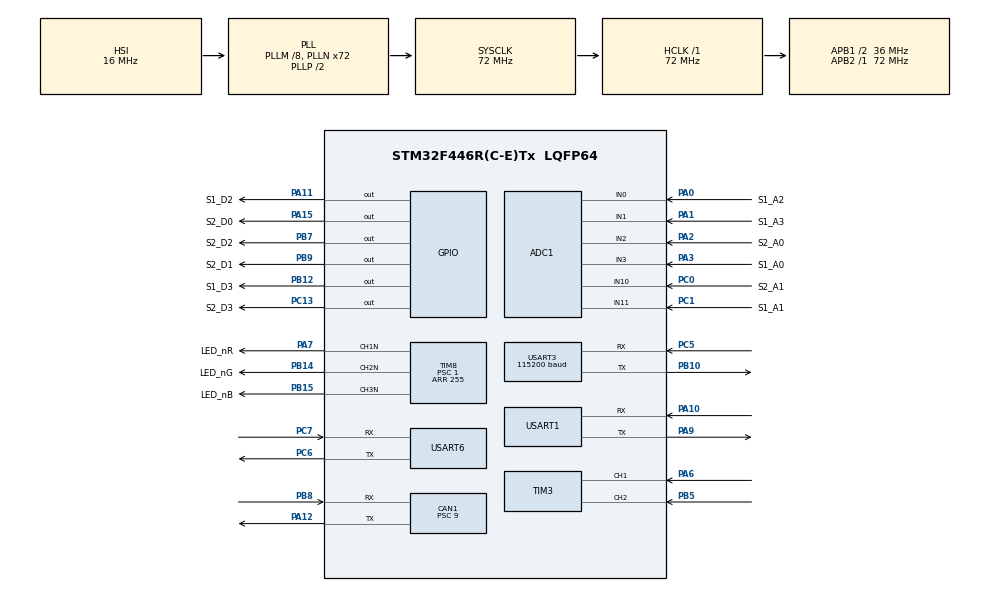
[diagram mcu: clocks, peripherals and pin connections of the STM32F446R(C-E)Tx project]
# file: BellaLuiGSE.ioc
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Dma.ADC1.4.FIFOMode=DMA_FIFOMODE_DISABLE
CAN1.NART=DISABLE
Dma.ADC1.4.Priority=DMA_PRIORITY_LOW
PH0-OSC_IN.Signal=RCC_OSC_IN
PB10.GPIO_PuPd=GPIO_PULLUP
PB10.Mode=Asynchronous
PA10.GPIO_PuPd=GPIO_PULLUP
Dma.USART3_TX.3.MemInc=DMA_MINC_ENABLE
ADC1.SamplingTime-6\#ChannelRegularConversion=ADC_SAMPLETIME_144CYCLES
PB14.GPIO_Label=LED_nG
PC5.Mode=Asynchronous
Dma.USART3_TX.3.MemDataAlignment=DMA_MDATAALIGN_BYTE
Dma.ADC1.4.PeriphInc=DMA_PINC_DISABLE
RCC.SYSCLKSource=RCC_SYSCLKSOURCE_PLLCLK
TIM8.OCNPolarity_1=TIM_OCNPOLARITY_LOW
Dma.USART3_RX.2.Priority=DMA_PRIORITY_LOW
TIM8.OCNPolarity_2=TIM_OCNPOLARITY_LOW
FREERTOS.configENABLE_FPU=1
USART3.BaudRate=115200
Dma.USART1_TX.0.Direction=DMA_MEMORY_TO_PERIPH
ADC1.Channel-5\#ChannelRegularConversion=ADC_CHANNEL_10
TIM8.OCNPolarity_3=TIM_OCNPOLARITY_LOW
RCC.APB2TimFreq_Value=72000000
ADC1.Channel-2\#ChannelRegularConversion=ADC_CHANNEL_3
PC7.Signal=USART6_RX
VP_TIM3_VS_ControllerModeClock.Mode=Clock Mode
Dma.ADC1.4.Instance=DMA2_Stream0
FREERTOS.configMINIMAL_STACK_SIZE=256
Dma.USART1_RX.1.PeriphDataAlignment=DMA_PDATAALIGN_BYTE
NVIC.TIM8_TRG_COM_TIM14_IRQn=true\:0\:0\:false\:false\:true\:false\:false\:true
PB3.Mode=Trace_Asynchronous_SW
PB12.GPIO_Label=S1_D3
TIM8.OCMode_PWM-PWM\ Generation2\ CH2N=TIM_OCMODE_PWM1
TIM8.OCMode_PWM-PWM\ Generation1\ CH1N=TIM_OCMODE_PWM1
PB14.Mode=PWM Generation2 CH2N
VP_FREERTOS_VS_CMSIS_V1.Mode=CMSIS_V1
VP_SYS_VS_tim14.Mode=TIM14
Dma.USART1_TX.0.PeriphDataAlignment=DMA_PDATAALIGN_BYTE
VP_TIM1_VS_ClockSourceINT.Mode=Internal
Dma.USART1_RX.1.Mode=DMA_CIRCULAR
CAN1.Prescaler=9
Mcu.Package=LQFP64
PB9.Signal=GPIO_Output
NVIC.TimeBase=TIM8_TRG_COM_TIM14_IRQn
NVIC.TimeBaseIP=TIM14
PA10.Signal=USART1_RX
Dma.ADC1.4.MemInc=DMA_MINC_ENABLE
PC6.GPIO_PuPd=GPIO_PULLUP
Dma.USART1_RX.1.PeriphInc=DMA_PINC_DISABLE
NVIC.DMA2_Stream2_IRQn=true\:5\:0\:false\:false\:true\:false\:false\:true
RCC.APB1TimFreq_Value=72000000
NVIC.USART1_IRQn=true\:0\:0\:false\:false\:true\:true\:true\:true
ADC1.Rank-4\#ChannelRegularConversion=3
CAN1.CalculateTimeQuantum=250.0
Dma.USART1_RX.1.Instance=DMA2_Stream2
Dma.USART1_RX.1.MemDataAlignment=DMA_MDATAALIGN_BYTE
FREERTOS.Tasks01=defaultTask,0,256,StartDefaultTask,Default,NULL,Dynamic,NULL,NULL
TIM3.Channel-Input_Capture2_from_TI2=TIM_CHANNEL_2
PC13.Signal=GPIO_Output
PC6.Signal=USART6_TX
PA11.GPIO_Label=S1_D2
PC0.Signal=ADCx_IN10
RCC.APB1CLKDivider=RCC_HCLK_DIV2
PC14-OSC32_IN.Signal=RCC_OSC32_IN
Dma.USART3_TX.3.PeriphInc=DMA_PINC_DISABLE
PA0-WKUP.GPIO_Label=S1_A2
PA0-WKUP.Signal=ADCx_IN0
ADC1.Channel-7\#ChannelRegularConversion=ADC_CHANNEL_1
Dma.USART3_RX.2.PeriphDataAlignment=DMA_PDATAALIGN_BYTE
PC6.Mode=Asynchronous
TIM8.Channel-PWM\ Generation3\ CH3N=TIM_CHANNEL_3
PA9.Signal=USART1_TX
VP_TIM8_VS_ClockSourceINT.Mode=Internal
PC7.GPIO_PuPd=GPIO_PULLUP
PB10.Signal=USART3_TX
PB14.Signal=TIM8_CH2N
Dma.USART1_RX.1.FIFOMode=DMA_FIFOMODE_DISABLE
FREERTOS.MEMORY_ALLOCATION=0
PB15.GPIO_Label=LED_nB
PA1.GPIO_Label=S1_A3
Dma.ADC1.4.Mode=DMA_CIRCULAR
ADC1.DMAContinuousRequests=ENABLE
PA13.Mode=Trace_Asynchronous_SW
Dma.ADC1.4.MemDataAlignment=DMA_MDATAALIGN_HALFWORD
Dma.USART3_TX.3.Mode=DMA_NORMAL
TIM8.Period=255
PB5.Signal=S_TIM3_CH2
ADC1.master=1
USART1.VirtualMode=VM_ASYNC
PA11.Signal=GPIO_Output
ProjectManager.HeapSize=0x200
ADC1.SamplingTime-5\#ChannelRegularConversion=ADC_SAMPLETIME_144CYCLES
NVIC.PriorityGroup=NVIC_PRIORITYGROUP_4
PB8.Mode=Master
Dma.USART1_RX.1.Direction=DMA_PERIPH_TO_MEMORY
ADC1.Rank-5\#ChannelRegularConversion=4
PC1.Signal=ADCx_IN11
NVIC.CAN1_RX0_IRQn=true\:0\:0\:false\:false\:true\:true\:true\:true
Dma.USART3_TX.3.Priority=DMA_PRIORITY_LOW
Mcu.Family=STM32F4
RCC.CortexFreq_Value=72000000
Dma.USART3_TX.3.PeriphDataAlignment=DMA_PDATAALIGN_BYTE
ADC1.ContinuousConvMode=ENABLE
SH.ADCx_IN2.0=ADC1_IN2,IN2
VP_IWDG_VS_IWDG.Mode=IWDG_Activate
PC0.GPIO_Label=S2_A1
PC13.GPIO_Label=S2_D3
PB15.Signal=TIM8_CH3N
ProjectManager.StackSize=0x400
PA15.GPIO_Label=S2_D0
Dma.USART1_TX.0.Priority=DMA_PRIORITY_LOW
PA12.Signal=CAN1_TX
ADC1.Channel-3\#ChannelRegularConversion=ADC_CHANNEL_11
Dma.USART3_RX.2.PeriphInc=DMA_PINC_DISABLE
RCC.HCLKFreq_Value=72000000
SH.ADCx_IN3.0=ADC1_IN3,IN3
NVIC.DMA2_Stream0_IRQn=true\:0\:0\:false\:false\:true\:true\:false\:true
Dma.USART1_RX.1.MemInc=DMA_MINC_ENABLE
RCC.AHBFreq_Value=72000000
PH0-OSC_IN.Mode=HSE-External-Oscillator
RCC.HSE_VALUE=8000000
ADC1.SamplingTime-4\#ChannelRegularConversion=ADC_SAMPLETIME_144CYCLES
ADC1.Channel-6\#ChannelRegularConversion=ADC_CHANNEL_0
ADC1.Rank-2\#ChannelRegularConversion=1
Dma.USART3_TX.3.Direction=DMA_MEMORY_TO_PERIPH
PC14-OSC32_IN.Mode=LSE-External-Oscillator
PA14.Mode=Trace_Asynchronous_SW
TIM8.Pulse-PWM\ Generation2\ CH2N=128
PB7.Signal=GPIO_Output
SH.ADCx_IN0.0=ADC1_IN0,IN0
SH.S_TIM3_CH1.0=TIM3_CH1,TriggerSource_TI1FP1
FREERTOS.configTOTAL_HEAP_SIZE=30720
PB7.GPIO_Label=S2_D2
PH1-OSC_OUT.Mode=HSE-External-Oscillator
PA6.Signal=S_TIM3_CH1
NVIC.DMA2_Stream7_IRQn=true\:5\:0\:false\:false\:true\:false\:true\:true
USART6.VirtualMode=VM_ASYNC
PA2.GPIO_Label=S2_A0
IWDG.Reload=2000
TIM8.Channel-PWM\ Generation2\ CH2N=TIM_CHANNEL_2
PA15.Signal=GPIO_Output
Dma.USART1_TX.0.Instance=DMA2_Stream7
Dma.USART1_TX.0.FIFOMode=DMA_FIFOMODE_DISABLE
TIM8.Prescaler=1
SH.ADCx_IN1.0=ADC1_IN1,IN1
Dma.Request2=USART3_RX
Dma.Request1=USART1_RX
Dma.Request4=ADC1
Dma.Request3=USART3_TX
PC5.Signal=USART3_RX
Dma.USART1_RX.1.Priority=DMA_PRIORITY_LOW
ADC1.Rank-6\#ChannelRegularConversion=5
Dma.Request0=USART1_TX
TIM8.Pulse-PWM\ Generation1\ CH1N=128
PA3.Signal=ADCx_IN3
PC15-OSC32_OUT.Mode=LSE-External-Oscillator
Dma.USART1_TX.0.MemInc=DMA_MINC_ENABLE
PA7.Mode=PWM Generation1 CH1N
Dma.USART1_TX.0.PeriphInc=DMA_PINC_DISABLE
ADC1.Channel-4\#ChannelRegularConversion=ADC_CHANNEL_2
PB9.GPIO_Label=S2_D1
PA10.Mode=Asynchronous
Dma.USART3_RX.2.Mode=DMA_CIRCULAR
Dma.ADC1.4.PeriphDataAlignment=DMA_PDATAALIGN_HALFWORD
NVIC.DMA1_Stream1_IRQn=true\:5\:0\:false\:false\:true\:false\:true\:true
PC5.GPIO_PuPd=GPIO_PULLUP
PA9.GPIO_PuPd=GPIO_PULLUP
ADC1.SamplingTime-2\#ChannelRegularConversion=ADC_SAMPLETIME_144CYCLES
TIM8.Channel-PWM\ Generation1\ CH1N=TIM_CHANNEL_1
PA13.Signal=SYS_JTMS-SWDIO
PA9.Mode=Asynchronous
Dma.USART3_RX.2.MemInc=DMA_MINC_ENABLE
CAN1.BS2=CAN_BS2_2TQ
CAN1.BS1=CAN_BS1_13TQ
ProjectManager.TargetToolchain=STM32CubeIDE
Dma.USART3_TX.3.FIFOMode=DMA_FIFOMODE_DISABLE
RCC.USBFreq_Value=72000000
Dma.USART3_RX.2.Direction=DMA_PERIPH_TO_MEMORY
PC15-OSC32_OUT.Signal=RCC_OSC32_OUT
PA1.Signal=ADCx_IN1
SH.S_TIM3_CH2.0=TIM3_CH2,Input_Capture2_from_TI2
Dma.USART3_TX.3.Instance=DMA1_Stream3
Dma.USART1_TX.0.Mode=DMA_NORMAL
board=custom
RCC.VCOOutputFreq_Value=144000000
TIM8.OCMode_PWM-PWM\ Generation3\ CH3N=TIM_OCMODE_PWM1
PB15.Mode=PWM Generation3 CH3N
RCC.APB2Freq_Value=72000000
SH.ADCx_IN11.0=ADC1_IN11,IN11
TIM8.Pulse-PWM\ Generation3\ CH3N=128
PC1.GPIO_Label=S1_A1
PH1-OSC_OUT.Signal=RCC_OSC_OUT
ADC1.NbrOfConversion=6
Mcu.Name=STM32F446R(C-E)Tx
PA2.Signal=ADCx_IN2
PB3.Signal=SYS_JTDO-SWO
RCC.SYSCLKFreq_VALUE=72000000
PA7.GPIO_Label=LED_nR
PA12.Mode=Master
ADC1.Rank-3\#ChannelRegularConversion=2
ADC1.SamplingTime-3\#ChannelRegularConversion=ADC_SAMPLETIME_144CYCLES
USART3.VirtualMode=VM_ASYNC
Dma.USART1_TX.0.MemDataAlignment=DMA_MDATAALIGN_BYTE
PA14.Signal=SYS_JTCK-SWCLK
SH.ADCx_IN10.0=ADC1_IN10,IN10
Dma.USART3_RX.2.FIFOMode=DMA_FIFOMODE_DISABLE
Dma.ADC1.4.Direction=DMA_PERIPH_TO_MEMORY
ADC1.Rank-7\#ChannelRegularConversion=6
Dma.USART3_RX.2.MemDataAlignment=DMA_MDATAALIGN_BYTE
ADC1.NbrOfConversionFlag=1
RCC.PLLM=8
RCC.PLLN=72
PB8.Signal=CAN1_RX
NVIC.DMA1_Stream3_IRQn=true\:5\:0\:false\:false\:true\:false\:true\:true
ADC1.SamplingTime-7\#ChannelRegularConversion=ADC_SAMPLETIME_144CYCLES
Dma.USART3_RX.2.Instance=DMA1_Stream1
PC7.Mode=Asynchronous
RCC.APB1Freq_Value=36000000
VP_CRC_VS_CRC.Mode=CRC_Activate
PB12.Signal=GPIO_Output
PA3.GPIO_Label=S1_A0
PA7.Signal=TIM8_CH1N

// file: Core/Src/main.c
/* USER CODE BEGIN Header */
/**
  ******************************************************************************
  * @file           : main.c
  * @brief          : Main program body
  ******************************************************************************
  * @attention
  *
  * <h2><center>&copy; Copyright (c) 2021 STMicroelectronics.
  * All rights reserved.</center></h2>
  *
  * This software component is licensed by ST under BSD 3-Clause license,
  * the "License"; You may not use this file except in compliance with the
  * License. You may obtain a copy of the License at:
  *                        opensource.org/licenses/BSD-3-Clause
  *
  ******************************************************************************
  */
/* USER CODE END Header */
#include "main.h"
#include "cmsis_os.h"
#include "FreeRTOS.h"

/* USER CODE BEGIN Includes */
#include "thread_init.h"
#include "can_transmission.h"
#include "debug/led.h"
#include "debug/console.h"
#include "debug/shell.h"
#include "debug/terminal.h"
/* USER CODE END Includes */

ADC_HandleTypeDef hadc1;
DMA_HandleTypeDef hdma_adc1;

CAN_HandleTypeDef hcan1;

CRC_HandleTypeDef hcrc;

TIM_HandleTypeDef htim1;
TIM_HandleTypeDef htim3;
TIM_HandleTypeDef htim8;

UART_HandleTypeDef huart1;
UART_HandleTypeDef huart3;
UART_HandleTypeDef huart6;
DMA_HandleTypeDef hdma_usart1_tx;
DMA_HandleTypeDef hdma_usart1_rx;
DMA_HandleTypeDef hdma_usart3_rx;
DMA_HandleTypeDef hdma_usart3_tx;

osThreadId defaultTaskHandle;

void SystemClock_Config(void);
static void MX_GPIO_Init(void);
static void MX_DMA_Init(void);
static void MX_CAN1_Init(void);
static void MX_USART1_UART_Init(void);
static void MX_USART3_UART_Init(void);
static void MX_TIM1_Init(void);
static void MX_TIM3_Init(void);
static void MX_TIM8_Init(void);
static void MX_USART6_UART_Init(void);
static void MX_ADC1_Init(void);
static void MX_CRC_Init(void);
static void MX_IWDG_Init(void);
void StartDefaultTask(void const * argument);

int main(void)
{

  /* MCU Configuration--------------------------------------------------------*/

  /* Reset of all peripherals, Initializes the Flash interface and the Systick. */
  HAL_Init();

  /* Configure the system clock */
  SystemClock_Config();

  /* Initialize all configured peripherals */
  MX_GPIO_Init();
  MX_DMA_Init();
  MX_CAN1_Init();
  MX_USART1_UART_Init();
  MX_USART3_UART_Init();
  MX_TIM1_Init();
  MX_TIM3_Init();
  MX_TIM8_Init();
  MX_USART6_UART_Init();
  MX_ADC1_Init();
  MX_CRC_Init();
  MX_IWDG_Init();
  /* USER CODE BEGIN 2 */
  rocket_log_init(&huart3);
  shell_init(&huart3, &terminal_execute);

  rocket_boot_log("BellaLui v1.0\n\n");

  led_init();
  led_set_rgb(127, 255, 255);

  CAN_Config(CAN_ID); // A changer en fonction de la board
  /* USER CODE END 2 */

  /* Create the thread(s) */
  /* definition and creation of defaultTask */
  osThreadDef(defaultTask, StartDefaultTask, osPriorityNormal, 0, 256);
  defaultTaskHandle = osThreadCreate(osThread(defaultTask), NULL);

  /* USER CODE BEGIN RTOS_THREADS */
  /* add threads, ... */
  create_threads();

  /* USER CODE END RTOS_THREADS */

  /* Start scheduler */
  osKernelStart();

  /* We should never get here as control is now taken by the scheduler */
  /* Infinite loop */
  while (1)
  {

  }
}

void SystemClock_Config(void)
{
  RCC_OscInitTypeDef RCC_OscInitStruct = {0};
  RCC_ClkInitTypeDef RCC_ClkInitStruct = {0};

  /** Configure the main internal regulator output voltage
  */
  __HAL_RCC_PWR_CLK_ENABLE();
  __HAL_PWR_VOLTAGESCALING_CONFIG(PWR_REGULATOR_VOLTAGE_SCALE3);
  /** Initializes the RCC Oscillators according to the specified parameters
  * in the RCC_OscInitTypeDef structure.
  */
  RCC_OscInitStruct.OscillatorType = RCC_OSCILLATORTYPE_HSI|RCC_OSCILLATORTYPE_LSI;
  RCC_OscInitStruct.HSIState = RCC_HSI_ON;
  RCC_OscInitStruct.HSICalibrationValue = RCC_HSICALIBRATION_DEFAULT;
  RCC_OscInitStruct.LSIState = RCC_LSI_ON;
  RCC_OscInitStruct.PLL.PLLState = RCC_PLL_ON;
  RCC_OscInitStruct.PLL.PLLSource = RCC_PLLSOURCE_HSI;
  RCC_OscInitStruct.PLL.PLLM = 8;
  RCC_OscInitStruct.PLL.PLLN = 72;
  RCC_OscInitStruct.PLL.PLLP = RCC_PLLP_DIV2;
  RCC_OscInitStruct.PLL.PLLQ = 2;
  RCC_OscInitStruct.PLL.PLLR = 2;
  if (HAL_RCC_OscConfig(&RCC_OscInitStruct) != HAL_OK)
  {
    Error_Handler();
  }
  /** Initializes the CPU, AHB and APB buses clocks
  */
  RCC_ClkInitStruct.ClockType = RCC_CLOCKTYPE_HCLK|RCC_CLOCKTYPE_SYSCLK
                              |RCC_CLOCKTYPE_PCLK1|RCC_CLOCKTYPE_PCLK2;
  RCC_ClkInitStruct.SYSCLKSource = RCC_SYSCLKSOURCE_PLLCLK;
  RCC_ClkInitStruct.AHBCLKDivider = RCC_SYSCLK_DIV1;
  RCC_ClkInitStruct.APB1CLKDivider = RCC_HCLK_DIV2;
  RCC_ClkInitStruct.APB2CLKDivider = RCC_HCLK_DIV1;

  if (HAL_RCC_ClockConfig(&RCC_ClkInitStruct, FLASH_LATENCY_2) != HAL_OK)
  {
    Error_Handler();
  }
}

static void MX_ADC1_Init(void)
{

  ADC_ChannelConfTypeDef sConfig = {0};

  /** Configure the global features of the ADC (Clock, Resolution, Data Alignment and number of conversion)
  */
  hadc1.Instance = ADC1;
  hadc1.Init.ClockPrescaler = ADC_CLOCK_SYNC_PCLK_DIV2;
  hadc1.Init.Resolution = ADC_RESOLUTION_12B;
  hadc1.Init.ScanConvMode = ENABLE;
  hadc1.Init.ContinuousConvMode = ENABLE;
  hadc1.Init.DiscontinuousConvMode = DISABLE;
  hadc1.Init.ExternalTrigConvEdge = ADC_EXTERNALTRIGCONVEDGE_NONE;
  hadc1.Init.ExternalTrigConv = ADC_SOFTWARE_START;
  hadc1.Init.DataAlign = ADC_DATAALIGN_RIGHT;
#ifdef HB1_SENSOR_TELEMETRY_BOARD
  hadc1.Init.NbrOfConversion = 6;
#endif
 #ifdef HB2_CODE_BOARD
  hadc1.Init.NbrOfConversion = 2;
#endif
#ifdef HB3_POWER_BOARD
  hadc1.Init.NbrOfConversion = 4;
#endif
  hadc1.Init.DMAContinuousRequests = ENABLE;
  hadc1.Init.EOCSelection = ADC_EOC_SINGLE_CONV;
  if (HAL_ADC_Init(&hadc1) != HAL_OK)
  {
    Error_Handler();
  }
  /** Configure for the selected ADC regular channel its corresponding rank in the sequencer and its sample time.
  */
  sConfig.Channel = ADC_CHANNEL_3;
  sConfig.Rank = 1;
  sConfig.SamplingTime = ADC_SAMPLETIME_144CYCLES;
  if (HAL_ADC_ConfigChannel(&hadc1, &sConfig) != HAL_OK)
  {
    Error_Handler();
  }
  /** Configure for the selected ADC regular channel its corresponding rank in the sequencer and its sample time.
  */
  sConfig.Channel = ADC_CHANNEL_11;
  sConfig.Rank = 2;
  sConfig.SamplingTime = ADC_SAMPLETIME_144CYCLES;
  if (HAL_ADC_ConfigChannel(&hadc1, &sConfig) != HAL_OK)
  {
    Error_Handler();
  }
  /** Configure for the selected ADC regular channel its corresponding rank in the sequencer and its sample time.
  */
#if defined (HB3_POWER_BOARD) || defined (HB1_SENSOR_TELEMETRY_BOARD)
  sConfig.Channel = ADC_CHANNEL_2;
  sConfig.Rank = 3;
  sConfig.SamplingTime = ADC_SAMPLETIME_144CYCLES;
  if (HAL_ADC_ConfigChannel(&hadc1, &sConfig) != HAL_OK)
  {
    Error_Handler();
  }
  /** Configure for the selected ADC regular channel its corresponding rank in the sequencer and its sample time.
  */
  sConfig.Channel = ADC_CHANNEL_10;
  sConfig.Rank = 4;
  sConfig.SamplingTime = ADC_SAMPLETIME_144CYCLES;
  if(HAL_ADC_ConfigChannel(&hadc1, &sConfig) != HAL_OK)
  {
    Error_Handler();
  }
#endif
  /** Configure for the selected ADC regular channel its corresponding rank in the sequencer and its sample time.
  */
#ifdef HB1_SENSOR_TELEMETRY_BOARD
  sConfig.Channel = ADC_CHANNEL_0;
  sConfig.Rank = 5;
  sConfig.SamplingTime = ADC_SAMPLETIME_144CYCLES;
  if (HAL_ADC_ConfigChannel(&hadc1, &sConfig) != HAL_OK)
  {
    Error_Handler();
  }
  /** Configure for the selected ADC regular channel its corresponding rank in the sequencer and its sample time.
  */
  sConfig.Channel = ADC_CHANNEL_1;
  sConfig.Rank = 6;
  sConfig.SamplingTime = ADC_SAMPLETIME_144CYCLES;
  if (HAL_ADC_ConfigChannel(&hadc1, &sConfig) != HAL_OK)
  {
    Error_Handler();
  }
#endif

}

static void MX_CAN1_Init(void)
{

  hcan1.Instance = CAN1;
  hcan1.Init.Prescaler = 9;
  hcan1.Init.Mode = CAN_MODE_NORMAL;
  hcan1.Init.SyncJumpWidth = CAN_SJW_1TQ;
  hcan1.Init.TimeSeg1 = CAN_BS1_13TQ;
  hcan1.Init.TimeSeg2 = CAN_BS2_2TQ;
  hcan1.Init.TimeTriggeredMode = DISABLE;
  hcan1.Init.AutoBusOff = DISABLE;
  hcan1.Init.AutoWakeUp = DISABLE;
  hcan1.Init.AutoRetransmission = DISABLE;
  hcan1.Init.ReceiveFifoLocked = DISABLE;
  hcan1.Init.TransmitFifoPriority = DISABLE;
  if (HAL_CAN_Init(&hcan1) != HAL_OK)
  {
    Error_Handler();
  }

}

static void MX_CRC_Init(void)
{

  hcrc.Instance = CRC;
  if (HAL_CRC_Init(&hcrc) != HAL_OK)
  {
    Error_Handler();
  }

}

static void MX_IWDG_Init(void)
{

// Setup for 1s reset
  hiwdg.Instance = IWDG;
  hiwdg.Init.Prescaler = IWDG_PRESCALER_8;
  hiwdg.Init.Reload = 200;
  if (HAL_IWDG_Init(&hiwdg) != HAL_OK)
  {
    Error_Handler();
  }

}

static void MX_TIM1_Init(void)
{

  TIM_ClockConfigTypeDef sClockSourceConfig = {0};
  TIM_MasterConfigTypeDef sMasterConfig = {0};

  htim1.Instance = TIM1;
  htim1.Init.Prescaler = 0;
  htim1.Init.CounterMode = TIM_COUNTERMODE_UP;
  htim1.Init.Period = 65535;
  htim1.Init.ClockDivision = TIM_CLOCKDIVISION_DIV1;
  htim1.Init.RepetitionCounter = 0;
  htim1.Init.AutoReloadPreload = TIM_AUTORELOAD_PRELOAD_DISABLE;
  if (HAL_TIM_Base_Init(&htim1) != HAL_OK)
  {
    Error_Handler();
  }
  sClockSourceConfig.ClockSource = TIM_CLOCKSOURCE_INTERNAL;
  if (HAL_TIM_ConfigClockSource(&htim1, &sClockSourceConfig) != HAL_OK)
  {
    Error_Handler();
  }
  sMasterConfig.MasterOutputTrigger = TIM_TRGO_RESET;
  sMasterConfig.MasterSlaveMode = TIM_MASTERSLAVEMODE_DISABLE;
  if (HAL_TIMEx_MasterConfigSynchronization(&htim1, &sMasterConfig) != HAL_OK)
  {
    Error_Handler();
  }

}

static void MX_TIM3_Init(void)
{

  TIM_SlaveConfigTypeDef sSlaveConfig = {0};
  TIM_MasterConfigTypeDef sMasterConfig = {0};
  TIM_IC_InitTypeDef sConfigIC = {0};

  htim3.Instance = TIM3;
  htim3.Init.Prescaler = 0;
  htim3.Init.CounterMode = TIM_COUNTERMODE_UP;
  htim3.Init.Period = 65535;
  htim3.Init.ClockDivision = TIM_CLOCKDIVISION_DIV1;
  htim3.Init.AutoReloadPreload = TIM_AUTORELOAD_PRELOAD_DISABLE;
  if (HAL_TIM_Base_Init(&htim3) != HAL_OK)
  {
    Error_Handler();
  }
  if (HAL_TIM_IC_Init(&htim3) != HAL_OK)
  {
    Error_Handler();
  }
  sSlaveConfig.SlaveMode = TIM_SLAVEMODE_EXTERNAL1;
  sSlaveConfig.InputTrigger = TIM_TS_TI1FP1;
  sSlaveConfig.TriggerPolarity = TIM_TRIGGERPOLARITY_RISING;
  sSlaveConfig.TriggerFilter = 0;
  if (HAL_TIM_SlaveConfigSynchro(&htim3, &sSlaveConfig) != HAL_OK)
  {
    Error_Handler();
  }
  sMasterConfig.MasterOutputTrigger = TIM_TRGO_RESET;
  sMasterConfig.MasterSlaveMode = TIM_MASTERSLAVEMODE_DISABLE;
  if (HAL_TIMEx_MasterConfigSynchronization(&htim3, &sMasterConfig) != HAL_OK)
  {
    Error_Handler();
  }
  sConfigIC.ICPolarity = TIM_INPUTCHANNELPOLARITY_RISING;
  sConfigIC.ICSelection = TIM_ICSELECTION_DIRECTTI;
  sConfigIC.ICPrescaler = TIM_ICPSC_DIV1;
  sConfigIC.ICFilter = 0;
  if (HAL_TIM_IC_ConfigChannel(&htim3, &sConfigIC, TIM_CHANNEL_2) != HAL_OK)
  {
    Error_Handler();
  }

}

static void MX_TIM8_Init(void)
{

  TIM_ClockConfigTypeDef sClockSourceConfig = {0};
  TIM_MasterConfigTypeDef sMasterConfig = {0};
  TIM_OC_InitTypeDef sConfigOC = {0};
  TIM_BreakDeadTimeConfigTypeDef sBreakDeadTimeConfig = {0};

  htim8.Instance = TIM8;
  htim8.Init.Prescaler = 1;
  htim8.Init.CounterMode = TIM_COUNTERMODE_UP;
  htim8.Init.Period = 255;
  htim8.Init.ClockDivision = TIM_CLOCKDIVISION_DIV1;
  htim8.Init.RepetitionCounter = 0;
  htim8.Init.AutoReloadPreload = TIM_AUTORELOAD_PRELOAD_DISABLE;
  if (HAL_TIM_Base_Init(&htim8) != HAL_OK)
  {
    Error_Handler();
  }
  sClockSourceConfig.ClockSource = TIM_CLOCKSOURCE_INTERNAL;
  if (HAL_TIM_ConfigClockSource(&htim8, &sClockSourceConfig) != HAL_OK)
  {
    Error_Handler();
  }
  if (HAL_TIM_PWM_Init(&htim8) != HAL_OK)
  {
    Error_Handler();
  }
  sMasterConfig.MasterOutputTrigger = TIM_TRGO_RESET;
  sMasterConfig.MasterSlaveMode = TIM_MASTERSLAVEMODE_DISABLE;
  if (HAL_TIMEx_MasterConfigSynchronization(&htim8, &sMasterConfig) != HAL_OK)
  {
    Error_Handler();
  }
  sConfigOC.OCMode = TIM_OCMODE_PWM1;
  sConfigOC.Pulse = 128;
  sConfigOC.OCPolarity = TIM_OCPOLARITY_HIGH;
  sConfigOC.OCNPolarity = TIM_OCNPOLARITY_LOW;
  sConfigOC.OCFastMode = TIM_OCFAST_DISABLE;
  sConfigOC.OCIdleState = TIM_OCIDLESTATE_RESET;
  sConfigOC.OCNIdleState = TIM_OCNIDLESTATE_RESET;
  if (HAL_TIM_PWM_ConfigChannel(&htim8, &sConfigOC, TIM_CHANNEL_1) != HAL_OK)
  {
    Error_Handler();
  }
  if (HAL_TIM_PWM_ConfigChannel(&htim8, &sConfigOC, TIM_CHANNEL_2) != HAL_OK)
  {
    Error_Handler();
  }
  if (HAL_TIM_PWM_ConfigChannel(&htim8, &sConfigOC, TIM_CHANNEL_3) != HAL_OK)
  {
    Error_Handler();
  }
  sBreakDeadTimeConfig.OffStateRunMode = TIM_OSSR_DISABLE;
  sBreakDeadTimeConfig.OffStateIDLEMode = TIM_OSSI_DISABLE;
  sBreakDeadTimeConfig.LockLevel = TIM_LOCKLEVEL_OFF;
  sBreakDeadTimeConfig.DeadTime = 0;
  sBreakDeadTimeConfig.BreakState = TIM_BREAK_DISABLE;
  sBreakDeadTimeConfig.BreakPolarity = TIM_BREAKPOLARITY_HIGH;
  sBreakDeadTimeConfig.AutomaticOutput = TIM_AUTOMATICOUTPUT_DISABLE;
  if (HAL_TIMEx_ConfigBreakDeadTime(&htim8, &sBreakDeadTimeConfig) != HAL_OK)
  {
    Error_Handler();
  }
  HAL_TIM_MspPostInit(&htim8);

}

static void MX_USART1_UART_Init(void)
{

  huart1.Instance = USART1;
  huart1.Init.BaudRate = 115200;
  huart1.Init.WordLength = UART_WORDLENGTH_8B;
  huart1.Init.StopBits = UART_STOPBITS_1;
  huart1.Init.Parity = UART_PARITY_NONE;
  huart1.Init.Mode = UART_MODE_TX_RX;
  huart1.Init.HwFlowCtl = UART_HWCONTROL_NONE;
  huart1.Init.OverSampling = UART_OVERSAMPLING_16;
  if (HAL_UART_Init(&huart1) != HAL_OK)
  {
    Error_Handler();
  }

}

static void MX_USART3_UART_Init(void)
{

  huart3.Instance = USART3;
  huart3.Init.BaudRate = 115200;
  huart3.Init.WordLength = UART_WORDLENGTH_8B;
  huart3.Init.StopBits = UART_STOPBITS_1;
  huart3.Init.Parity = UART_PARITY_NONE;
  huart3.Init.Mode = UART_MODE_TX_RX;
  huart3.Init.HwFlowCtl = UART_HWCONTROL_NONE;
  huart3.Init.OverSampling = UART_OVERSAMPLING_16;
  if (HAL_UART_Init(&huart3) != HAL_OK)
  {
    Error_Handler();
  }

}

static void MX_USART6_UART_Init(void)
{

  huart6.Instance = USART6;
  huart6.Init.BaudRate = 115200;
  huart6.Init.WordLength = UART_WORDLENGTH_8B;
  huart6.Init.StopBits = UART_STOPBITS_1;
  huart6.Init.Parity = UART_PARITY_NONE;
  huart6.Init.Mode = UART_MODE_TX_RX;
  huart6.Init.HwFlowCtl = UART_HWCONTROL_NONE;
  huart6.Init.OverSampling = UART_OVERSAMPLING_16;
  if (HAL_UART_Init(&huart6) != HAL_OK)
  {
    Error_Handler();
  }

}

static void MX_DMA_Init(void)
{

  /* DMA controller clock enable */
  __HAL_RCC_DMA2_CLK_ENABLE();
  __HAL_RCC_DMA1_CLK_ENABLE();

  /* DMA interrupt init */
  /* DMA1_Stream1_IRQn interrupt configuration */
  HAL_NVIC_SetPriority(DMA1_Stream1_IRQn, 5, 0);
  HAL_NVIC_EnableIRQ(DMA1_Stream1_IRQn);
  /* DMA1_Stream3_IRQn interrupt configuration */
  HAL_NVIC_SetPriority(DMA1_Stream3_IRQn, 5, 0);
  HAL_NVIC_EnableIRQ(DMA1_Stream3_IRQn);
  /* DMA2_Stream0_IRQn interrupt configuration */
  HAL_NVIC_SetPriority(DMA2_Stream0_IRQn, 5, 0);
  HAL_NVIC_EnableIRQ(DMA2_Stream0_IRQn);
  /* DMA2_Stream2_IRQn interrupt configuration */
  HAL_NVIC_SetPriority(DMA2_Stream2_IRQn, 5, 0);
  HAL_NVIC_EnableIRQ(DMA2_Stream2_IRQn);
  /* DMA2_Stream7_IRQn interrupt configuration */
  HAL_NVIC_SetPriority(DMA2_Stream7_IRQn, 5, 0);
  HAL_NVIC_EnableIRQ(DMA2_Stream7_IRQn);

}

static void MX_GPIO_Init(void)
{
  GPIO_InitTypeDef GPIO_InitStruct = {0};

  /* GPIO Ports Clock Enable */
  __HAL_RCC_GPIOC_CLK_ENABLE();
  __HAL_RCC_GPIOH_CLK_ENABLE();
  __HAL_RCC_GPIOA_CLK_ENABLE();
  __HAL_RCC_GPIOB_CLK_ENABLE();

#ifdef HB2_CODE_BOARD
  /*Configure GPIO pin Output Level */
  HAL_GPIO_WritePin(GPIOA, S1_D0_Pin|S1_D1_Pin|S1_D2_Pin, GPIO_PIN_RESET);

  /*Configure GPIO pin Output Level */
  HAL_GPIO_WritePin(S1_D3_GPIO_Port, S1_D3_Pin, GPIO_PIN_RESET);

  /*Configure GPIO pin : S2_D3_Pin */
  GPIO_InitStruct.Pin = S2_D3_Pin;
  GPIO_InitStruct.Mode = GPIO_MODE_INPUT;
  GPIO_InitStruct.Pull = GPIO_NOPULL;
  HAL_GPIO_Init(S2_D3_GPIO_Port, &GPIO_InitStruct);

  /*Configure GPIO pin : S2_D0_Pin */
  GPIO_InitStruct.Pin = S2_D0_Pin;
  GPIO_InitStruct.Mode = GPIO_MODE_INPUT;
  GPIO_InitStruct.Pull = GPIO_NOPULL;
  HAL_GPIO_Init(S2_D0_GPIO_Port, &GPIO_InitStruct);

  /*Configure GPIO pins : S2_D2_Pin S2_D1_Pin */
  GPIO_InitStruct.Pin = S2_D2_Pin|S2_D1_Pin;
  GPIO_InitStruct.Mode = GPIO_MODE_INPUT;
  GPIO_InitStruct.Pull = GPIO_NOPULL;
  HAL_GPIO_Init(GPIOB, &GPIO_InitStruct);
  /*Configure GPIO pins : S1_D0_Pin S1_D1_Pin S1_D2_Pin */
  GPIO_InitStruct.Pin = S1_D0_Pin|S1_D1_Pin|S1_D2_Pin;
  GPIO_InitStruct.Mode = GPIO_MODE_OUTPUT_PP;
  GPIO_InitStruct.Pull = GPIO_NOPULL;
  GPIO_InitStruct.Speed = GPIO_SPEED_FREQ_LOW;
  HAL_GPIO_Init(GPIOA, &GPIO_InitStruct);

  /*Configure GPIO pin : S1_D3_Pin */
  GPIO_InitStruct.Pin = S1_D3_Pin;
  GPIO_InitStruct.Mode = GPIO_MODE_OUTPUT_PP;
  GPIO_InitStruct.Pull = GPIO_NOPULL;
  GPIO_InitStruct.Speed = GPIO_SPEED_FREQ_LOW;
  HAL_GPIO_Init(S1_D3_GPIO_Port, &GPIO_InitStruct);
#endif

#ifdef HB1_SENSOR_TELEMETRY_BOARD
  /*Configure GPIO pin Output Level */
  HAL_GPIO_WritePin(S2_D3_GPIO_Port, S2_D3_Pin, GPIO_PIN_RESET);

  /*Configure GPIO pin Output Level */
  HAL_GPIO_WritePin(GPIOB, S1_D3_Pin|S2_D2_Pin|S2_D1_Pin, GPIO_PIN_RESET);

  /*Configure GPIO pin Output Level */
  HAL_GPIO_WritePin(GPIOA, S1_D2_Pin|S2_D0_Pin, GPIO_PIN_RESET);

  /*Configure GPIO pin : S2_D3_Pin */
  GPIO_InitStruct.Pin = S2_D3_Pin;
  GPIO_InitStruct.Mode = GPIO_MODE_OUTPUT_PP;
  GPIO_InitStruct.Pull = GPIO_NOPULL;
  GPIO_InitStruct.Speed = GPIO_SPEED_FREQ_LOW;
  HAL_GPIO_Init(S2_D3_GPIO_Port, &GPIO_InitStruct);

  /*Configure GPIO pins : S1_D3_Pin S2_D2_Pin S2_D1_Pin */
  GPIO_InitStruct.Pin = S1_D3_Pin|S2_D2_Pin|S2_D1_Pin;
  GPIO_InitStruct.Mode = GPIO_MODE_OUTPUT_PP;
  GPIO_InitStruct.Pull = GPIO_NOPULL;
  GPIO_InitStruct.Speed = GPIO_SPEED_FREQ_LOW;
  HAL_GPIO_Init(GPIOB, &GPIO_InitStruct);

  /*Configure GPIO pins : S1_D2_Pin S2_D0_Pin */
  GPIO_InitStruct.Pin = S1_D2_Pin|S2_D0_Pin;
  GPIO_InitStruct.Mode = GPIO_MODE_OUTPUT_PP;
  GPIO_InitStruct.Pull = GPIO_NOPULL;
  GPIO_InitStruct.Speed = GPIO_SPEED_FREQ_LOW;
  HAL_GPIO_Init(GPIOA, &GPIO_InitStruct);
#endif

#ifdef HB3_POWER_BOARD
  /*Configure GPIO pin Output Level */
    HAL_GPIO_WritePin(S2_D3_GPIO_Port, S2_D3_Pin, GPIO_PIN_RESET);

    /*Configure GPIO pin Output Level */
    HAL_GPIO_WritePin(GPIOB, S1_D3_Pin|S2_D2_Pin|S2_D1_Pin, GPIO_PIN_RESET);

    /*Configure GPIO pin Output Level */
    HAL_GPIO_WritePin(GPIOA, S1_D2_Pin|S2_D0_Pin|S1_D0_Pin|S1_D1_Pin, GPIO_PIN_RESET);

    /*Configure GPIO pin : S2_D3_Pin */
    GPIO_InitStruct.Pin = S2_D3_Pin;
    GPIO_InitStruct.Mode = GPIO_MODE_OUTPUT_PP;
    GPIO_InitStruct.Pull = GPIO_NOPULL;
    GPIO_InitStruct.Speed = GPIO_SPEED_FREQ_LOW;
    HAL_GPIO_Init(S2_D3_GPIO_Port, &GPIO_InitStruct);

    /*Configure GPIO pins : S1_D3_Pin S2_D2_Pin S2_D1_Pin */
    GPIO_InitStruct.Pin = S1_D3_Pin|S2_D2_Pin|S2_D1_Pin;
    GPIO_InitStruct.Mode = GPIO_MODE_OUTPUT_PP;
    GPIO_InitStruct.Pull = GPIO_NOPULL;
    GPIO_InitStruct.Speed = GPIO_SPEED_FREQ_LOW;
    HAL_GPIO_Init(GPIOB, &GPIO_InitStruct);

    /*Configure GPIO pins : S1_D2_Pin S2_D0_Pin S1_D0_Pin S1_D1_Pin */
    GPIO_InitStruct.Pin = S1_D2_Pin|S2_D0_Pin|S1_D0_Pin|S1_D1_Pin;
    GPIO_InitStruct.Mode = GPIO_MODE_OUTPUT_PP;
    GPIO_InitStruct.Pull = GPIO_NOPULL;
    GPIO_InitStruct.Speed = GPIO_SPEED_FREQ_LOW;
    HAL_GPIO_Init(GPIOA, &GPIO_InitStruct);
#endif
}

void StartDefaultTask(void const * argument)
{
  for(;;)
  {
    osDelay(1);
  }
}

void HAL_TIM_PeriodElapsedCallback(TIM_HandleTypeDef *htim)
{
  if (htim->Instance == TIM14) {
    HAL_IncTick();
  }
}

void Error_Handler(void)
{
  /* USER CODE BEGIN Error_Handler_Debug */
  /* User can add his own implementation to report the HAL error return state */
	led_set_rgb(255, 0, 0);
	HAL_NVIC_SystemReset();
  /* USER CODE END Error_Handler_Debug */
}

/************************ (C) COPYRIGHT STMicroelectronics *****END OF FILE****/
